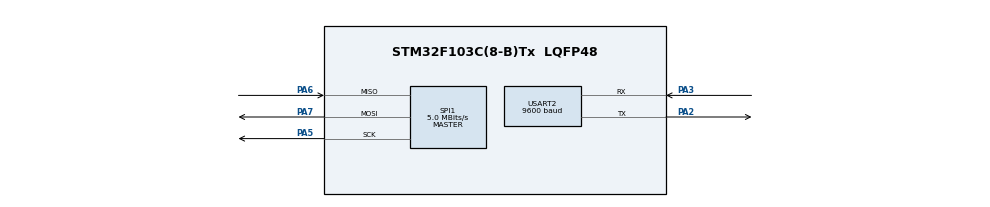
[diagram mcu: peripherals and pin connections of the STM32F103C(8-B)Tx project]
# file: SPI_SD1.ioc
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FATFS._MAX_SS=4096
FATFS._USE_LFN=1
Mcu.Family=STM32F1
Mcu.Name=STM32F103C(8-B)Tx
Mcu.Package=LQFP48
NVIC.PriorityGroup=NVIC_PRIORITYGROUP_4
PA13.Mode=Serial_Wire
PA13.Signal=SYS_JTMS-SWDIO
PA14.Mode=Serial_Wire
PA14.Signal=SYS_JTCK-SWCLK
PA2.Mode=Asynchronous
PA2.Signal=USART2_TX
PA3.Mode=Asynchronous
PA3.Signal=USART2_RX
PA5.Mode=Full_Duplex_Master
PA5.Signal=SPI1_SCK
PA6.Mode=Full_Duplex_Master
PA6.Signal=SPI1_MISO
PA7.Mode=Full_Duplex_Master
PA7.Signal=SPI1_MOSI
PD0-OSC_IN.Mode=HSE-External-Oscillator
PD0-OSC_IN.Signal=RCC_OSC_IN
PD1-OSC_OUT.Mode=HSE-External-Oscillator
PD1-OSC_OUT.Signal=RCC_OSC_OUT
ProjectManager.HeapSize=0x200
ProjectManager.StackSize=0x400
ProjectManager.TargetToolchain=MDK-ARM V5
RCC.AHBFreq_Value=40000000
RCC.APB1CLKDivider=RCC_HCLK_DIV2
RCC.APB1Freq_Value=20000000
RCC.APB1TimFreq_Value=40000000
RCC.APB2Freq_Value=40000000
RCC.APB2TimFreq_Value=40000000
RCC.HCLKFreq_Value=40000000
RCC.PLLMUL=RCC_PLL_MUL5
RCC.PLLSourceVirtual=RCC_PLLSOURCE_HSE
RCC.SYSCLKFreq_VALUE=40000000
RCC.SYSCLKSource=RCC_SYSCLKSOURCE_PLLCLK
RCC.USBFreq_Value=40000000
SPI1.BaudRatePrescaler=SPI_BAUDRATEPRESCALER_8
SPI1.CalculateBaudRate=5.0 MBits/s
SPI1.Direction=SPI_DIRECTION_2LINES
SPI1.Mode=SPI_MODE_MASTER
SPI1.VirtualType=VM_MASTER
USART2.BaudRate=9600
USART2.VirtualMode=VM_ASYNC
VP_FATFS_VS_Generic.Mode=User_defined
board=custom

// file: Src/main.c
/* USER CODE BEGIN Header */
/**
  ******************************************************************************
  * @file           : main.c
  * @brief          : Main program body
  ******************************************************************************
  * @attention
  *
  * <h2><center>&copy; Copyright (c) 2021 STMicroelectronics.
  * All rights reserved.</center></h2>
  *
  * This software component is licensed by ST under Ultimate Liberty license
  * SLA0044, the "License"; You may not use this file except in compliance with
  * the License. You may obtain a copy of the License at:
  *                             www.st.com/SLA0044
  *
  ******************************************************************************
  */
/* USER CODE END Header */

#include "main.h"
#include "fatfs.h"

/* USER CODE BEGIN Includes */
#include "sd.h"
#include "string.h"
/* USER CODE END Includes */

SPI_HandleTypeDef hspi1;

UART_HandleTypeDef huart2;
volatile uint16_t Timer1;
extern FATFS SDFatFs;

void SystemClock_Config(void);
static void MX_GPIO_Init(void);
static void MX_SPI1_Init(void);
static void MX_USART2_UART_Init(void);

/* USER CODE BEGIN 0 */
struct sd_data SD;
/* USER CODE END 0 */

int main(void)
{
  /* USER CODE BEGIN 1 */
	char p[] ="Hello\r\n";
  /* USER CODE END 1 */

  /* MCU Configuration--------------------------------------------------------*/

  /* Reset of all peripherals, Initializes the Flash interface and the Systick. */
  HAL_Init();

  /* Configure the system clock */
  SystemClock_Config();

  /* Initialize all configured peripherals */
  MX_GPIO_Init();
  MX_SPI1_Init();
  MX_FATFS_Init();
  MX_USART2_UART_Init();
  /* USER CODE BEGIN 2 */

	disk_initialize(SDFatFs.drv);
//	for(int i = 0; i < 10; i++){
//		SD_Write_File("File3.txt","Hello\r\n",9);
//		HAL_Delay(50);
//	}
//	if(!SD_Read_File("File3.txt")){
//		HAL_UART_Transmit(&huart2,(uint8_t*)"Error\r\n",9,1000);
//	}
//	//SD_creatSubDir("DATA");
	SD_List_File();
  /* USER CODE END 2 */

  /* Infinite loop */
  while (1)
  {
		//HAL_UART_Transmit(&huart2,(uint8_t*)p,strlen(p),1000);
  }
}

void SystemClock_Config(void)
{
  RCC_OscInitTypeDef RCC_OscInitStruct = {0};
  RCC_ClkInitTypeDef RCC_ClkInitStruct = {0};

  /** Initializes the CPU, AHB and APB busses clocks
  */
  RCC_OscInitStruct.OscillatorType = RCC_OSCILLATORTYPE_HSE;
  RCC_OscInitStruct.HSEState = RCC_HSE_ON;
  RCC_OscInitStruct.HSEPredivValue = RCC_HSE_PREDIV_DIV1;
  RCC_OscInitStruct.HSIState = RCC_HSI_ON;
  RCC_OscInitStruct.PLL.PLLState = RCC_PLL_ON;
  RCC_OscInitStruct.PLL.PLLSource = RCC_PLLSOURCE_HSE;
  RCC_OscInitStruct.PLL.PLLMUL = RCC_PLL_MUL9;
  if (HAL_RCC_OscConfig(&RCC_OscInitStruct) != HAL_OK)
  {
    Error_Handler();
  }
  /** Initializes the CPU, AHB and APB busses clocks
  */
  RCC_ClkInitStruct.ClockType = RCC_CLOCKTYPE_HCLK|RCC_CLOCKTYPE_SYSCLK
                              |RCC_CLOCKTYPE_PCLK1|RCC_CLOCKTYPE_PCLK2;
  RCC_ClkInitStruct.SYSCLKSource = RCC_SYSCLKSOURCE_PLLCLK;
  RCC_ClkInitStruct.AHBCLKDivider = RCC_SYSCLK_DIV1;
  RCC_ClkInitStruct.APB1CLKDivider = RCC_HCLK_DIV2;
  RCC_ClkInitStruct.APB2CLKDivider = RCC_HCLK_DIV1;

  if (HAL_RCC_ClockConfig(&RCC_ClkInitStruct, FLASH_LATENCY_2) != HAL_OK)
  {
    Error_Handler();
  }
}

static void MX_SPI1_Init(void)
{

  /* SPI1 parameter configuration*/
  hspi1.Instance = SPI1;
  hspi1.Init.Mode = SPI_MODE_MASTER;
  hspi1.Init.Direction = SPI_DIRECTION_2LINES;
  hspi1.Init.DataSize = SPI_DATASIZE_8BIT;
  hspi1.Init.CLKPolarity = SPI_POLARITY_LOW;
  hspi1.Init.CLKPhase = SPI_PHASE_1EDGE;
  hspi1.Init.NSS = SPI_NSS_SOFT;
  hspi1.Init.BaudRatePrescaler = SPI_BAUDRATEPRESCALER_8;
  hspi1.Init.FirstBit = SPI_FIRSTBIT_MSB;
  hspi1.Init.TIMode = SPI_TIMODE_DISABLE;
  hspi1.Init.CRCCalculation = SPI_CRCCALCULATION_DISABLE;
  hspi1.Init.CRCPolynomial = 10;
  if (HAL_SPI_Init(&hspi1) != HAL_OK)
  {
    Error_Handler();
  }

}

static void MX_USART2_UART_Init(void)
{

  huart2.Instance = USART2;
  huart2.Init.BaudRate = 9600;
  huart2.Init.WordLength = UART_WORDLENGTH_8B;
  huart2.Init.StopBits = UART_STOPBITS_1;
  huart2.Init.Parity = UART_PARITY_NONE;
  huart2.Init.Mode = UART_MODE_TX_RX;
  huart2.Init.HwFlowCtl = UART_HWCONTROL_NONE;
  huart2.Init.OverSampling = UART_OVERSAMPLING_16;
  if (HAL_UART_Init(&huart2) != HAL_OK)
  {
    Error_Handler();
  }

}

static void MX_GPIO_Init(void)
{
  GPIO_InitTypeDef GPIO_InitStruct = {0};

  /* GPIO Ports Clock Enable */
  __HAL_RCC_GPIOD_CLK_ENABLE();
  __HAL_RCC_GPIOA_CLK_ENABLE();
  __HAL_RCC_GPIOB_CLK_ENABLE();

  /*Configure GPIO pin Output Level */
  HAL_GPIO_WritePin(GPIOB, GPIO_PIN_0, GPIO_PIN_RESET);

  /*Configure GPIO pin : PB0 */
  GPIO_InitStruct.Pin = GPIO_PIN_0;
  GPIO_InitStruct.Mode = GPIO_MODE_OUTPUT_PP;
  GPIO_InitStruct.Pull = GPIO_NOPULL;
  GPIO_InitStruct.Speed = GPIO_SPEED_FREQ_LOW;
  HAL_GPIO_Init(GPIOB, &GPIO_InitStruct);

}

void Error_Handler(void)
{
}

/************************ (C) COPYRIGHT STMicroelectronics *****END OF FILE****/
